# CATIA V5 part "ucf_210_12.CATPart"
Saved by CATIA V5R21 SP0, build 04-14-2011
Part number: ucf_210_12
Bounding box of the stored display mesh (mm): x -16.987 to -4.644, y -6.35 to 6.35, z 27.115 to 39.459
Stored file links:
  C:\TPO v2\SharedFS\Outgoing\ucf_210_12.CATPart

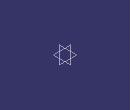
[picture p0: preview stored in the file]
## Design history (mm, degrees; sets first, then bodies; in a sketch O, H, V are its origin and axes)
AxisSystem1: origin (0, 0, 0), X (1, 0, 0), Y (0, 1, 0), Z (0, 0, 1)
Body1 "ucf_210_12" (main body)
  Solid1: solid without history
